One B-rep face of a CAD part: STEP entity #217.
In plain terms, the planar face has unit normal (1, 0, 0).
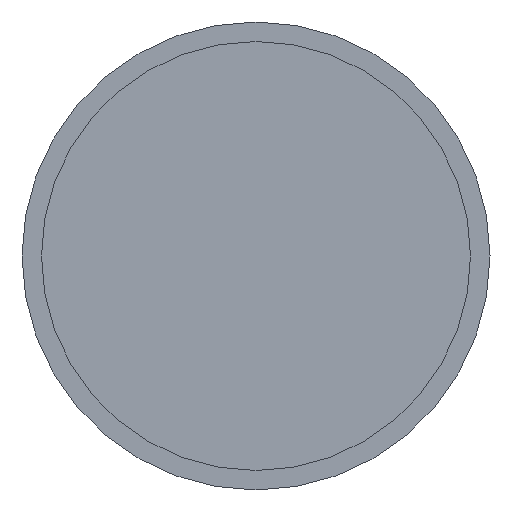
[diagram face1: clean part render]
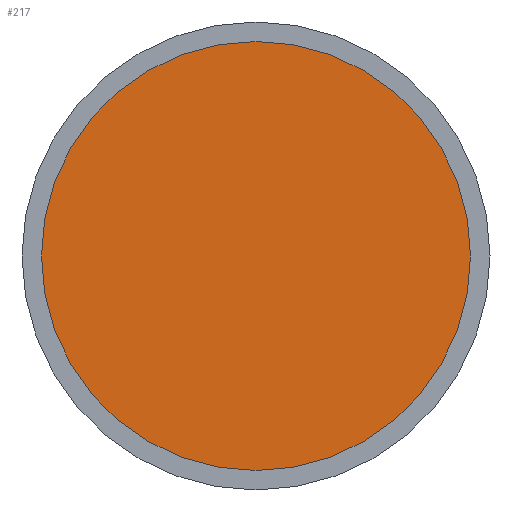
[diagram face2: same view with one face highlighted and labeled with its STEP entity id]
Its self-contained STEP definition (entity closure, numbers rounded to 3 decimals):
#151 = CYLINDRICAL_SURFACE('',#152,2.75);
#152 = AXIS2_PLACEMENT_3D('',#153,#154,#155);
#153 = CARTESIAN_POINT('',(-23.35,9.,15.));
#154 = DIRECTION('',(-1.,0.,0.));
#155 = DIRECTION('',(0.,0.,1.));
#168 = VERTEX_POINT('',#169);
#169 = CARTESIAN_POINT('',(-23.35,9.,17.75));
#190 = EDGE_CURVE('',#168,#168,#191,.T.);
#191 = SURFACE_CURVE('',#192,(#197,#204),.PCURVE_S1.);
#192 = CIRCLE('',#193,2.75);
#193 = AXIS2_PLACEMENT_3D('',#194,#195,#196);
#194 = CARTESIAN_POINT('',(-23.35,9.,15.));
#195 = DIRECTION('',(-1.,-0.,0.));
#196 = DIRECTION('',(0.,0.,1.));
#197 = PCURVE('',#151,#198);
#198 = DEFINITIONAL_REPRESENTATION('',(#199),#203);
#199 = LINE('',#200,#201);
#200 = CARTESIAN_POINT('',(0.,0.));
#201 = VECTOR('',#202,1.);
#202 = DIRECTION('',(1.,0.));
#203 = ( GEOMETRIC_REPRESENTATION_CONTEXT(2) 
PARAMETRIC_REPRESENTATION_CONTEXT() REPRESENTATION_CONTEXT('2D SPACE',''
  ) );
#204 = PCURVE('',#205,#210);
#205 = PLANE('',#206);
#206 = AXIS2_PLACEMENT_3D('',#207,#208,#209);
#207 = CARTESIAN_POINT('',(-23.35,9.,15.));
#208 = DIRECTION('',(-1.,0.,0.));
#209 = DIRECTION('',(0.,0.,1.));
#210 = DEFINITIONAL_REPRESENTATION('',(#211),#215);
#211 = CIRCLE('',#212,2.75);
#212 = AXIS2_PLACEMENT_2D('',#213,#214);
#213 = CARTESIAN_POINT('',(0.,0.));
#214 = DIRECTION('',(1.,0.));
#215 = ( GEOMETRIC_REPRESENTATION_CONTEXT(2) 
PARAMETRIC_REPRESENTATION_CONTEXT() REPRESENTATION_CONTEXT('2D SPACE',''
  ) );
#217 = ADVANCED_FACE('',(#218),#205,.F.);
#218 = FACE_BOUND('',#219,.T.);
#219 = EDGE_LOOP('',(#220));
#220 = ORIENTED_EDGE('',*,*,#190,.F.);
